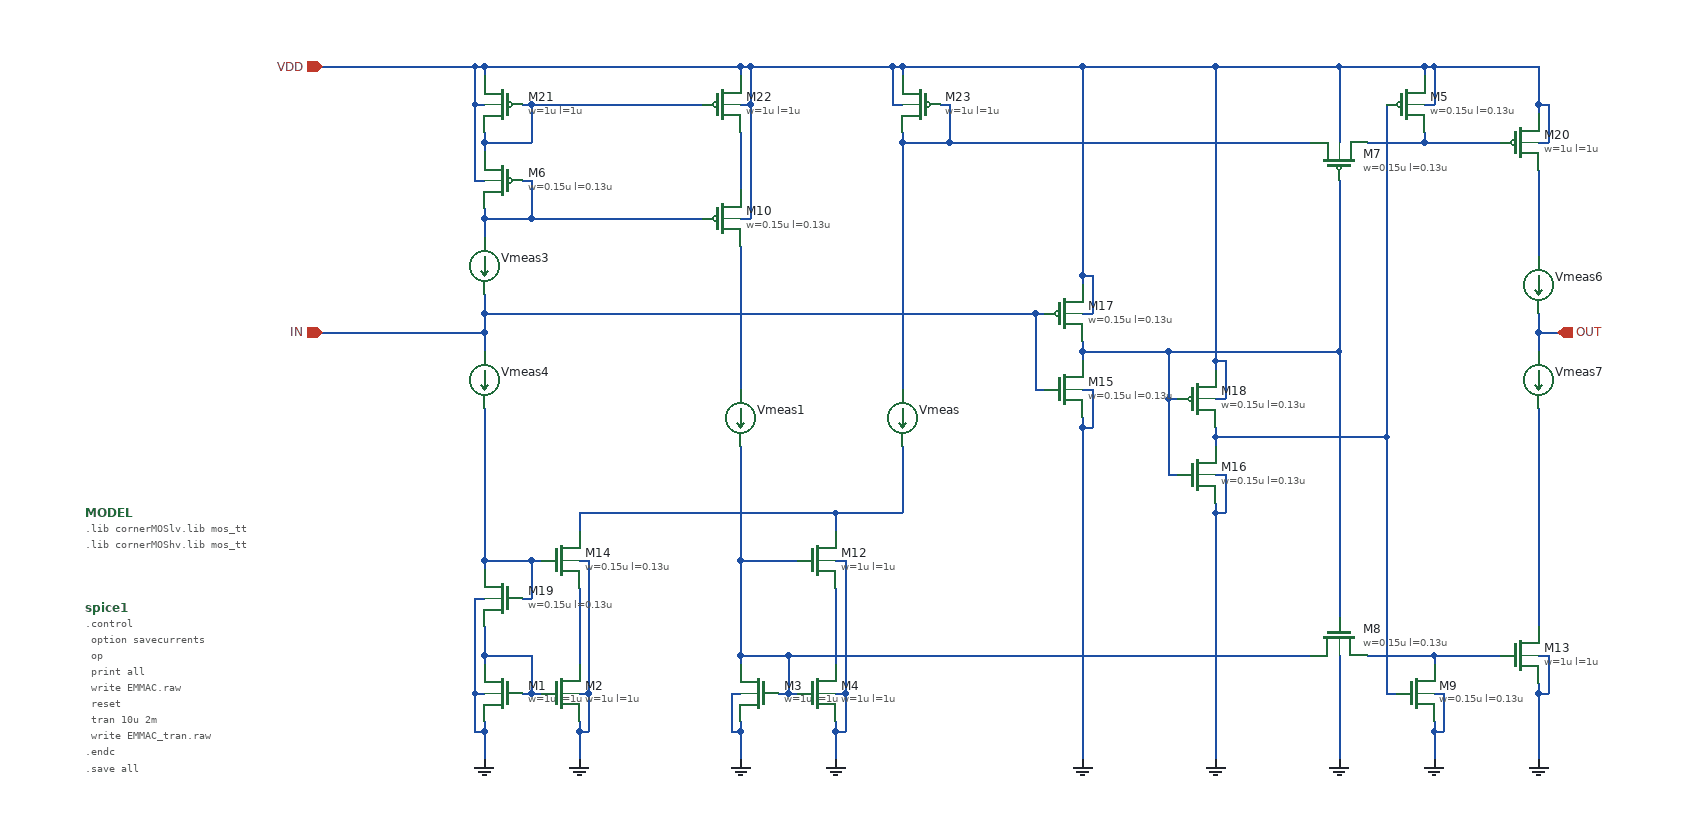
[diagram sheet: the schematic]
v {xschem version=3.4.8RC file_version=1.3}
G {}
K {}
V {}
S {}
F {}
E {}
N 390 280 400 280 {lab=#net1}
N 330 280 340 280 {lab=GND}
N 330 280 330 320 {lab=GND}
N 330 320 340 320 {lab=GND}
N 340 310 340 320 {lab=GND}
N 330 -380 330 -340 {lab=VDD}
N 330 -380 340 -380 {lab=VDD}
N 340 -380 340 -370 {lab=VDD}
N 380 -340 390 -340 {lab=#net2}
N 390 -340 390 -300 {lab=#net2}
N 340 -300 390 -300 {lab=#net2}
N 340 -310 340 -300 {lab=#net2}
N 610 -380 610 -370 {lab=VDD}
N 390 -340 570 -340 {lab=#net2}
N 610 -340 620 -340 {lab=VDD}
N 620 -380 620 -340 {lab=VDD}
N 610 -380 620 -380 {lab=VDD}
N 440 280 450 280 {lab=#net3}
N 450 280 450 320 {lab=#net3}
N 440 320 450 320 {lab=#net3}
N 440 310 440 320 {lab=#net3}
N 330 -340 340 -340 {lab=VDD}
N 380 180 390 180 {lab=#net4}
N 390 140 390 180 {lab=#net4}
N 440 320 440 350 {lab=#net3}
N 340 320 340 350 {lab=GND}
N 390 240 390 280 {lab=#net1}
N 380 280 390 280 {lab=#net1}
N 650 280 660 280 {lab=#net5}
N 660 240 660 280 {lab=#net5}
N 600 280 610 280 {lab=#net6}
N 600 280 600 320 {lab=#net6}
N 600 320 610 320 {lab=#net6}
N 610 310 610 320 {lab=#net6}
N 710 280 720 280 {lab=#net7}
N 720 280 720 320 {lab=#net7}
N 710 320 720 320 {lab=#net7}
N 710 310 710 320 {lab=#net7}
N 710 320 710 350 {lab=#net7}
N 610 320 610 350 {lab=#net6}
N 660 280 670 280 {lab=#net5}
N 770 -380 770 -340 {lab=VDD}
N 770 -380 780 -380 {lab=VDD}
N 780 -380 780 -370 {lab=VDD}
N 820 -340 830 -340 {lab=#net8}
N 770 -340 780 -340 {lab=VDD}
N 1450 240 1460 240 {lab=#net9}
N 340 -120 340 -100 {lab=IN}
N 1450 -100 1470 -100 {lab=OUT}
N 330 180 340 180 {lab=GND}
N 1110 50 1120 50 {lab=#net10}
N 1120 50 1120 90 {lab=#net10}
N 1110 90 1120 90 {lab=#net10}
N 1110 -70 1110 -60 {lab=VDD}
N 1110 -30 1120 -30 {lab=VDD}
N 1120 -70 1120 -30 {lab=VDD}
N 1110 -70 1120 -70 {lab=VDD}
N 1060 50 1070 50 {lab=#net11}
N 1060 -30 1070 -30 {lab=#net11}
N 620 -380 770 -380 {lab=VDD}
N 830 -340 830 -300 {lab=#net8}
N 1460 240 1460 280 {lab=#net9}
N 1450 280 1460 280 {lab=#net9}
N 1450 270 1450 280 {lab=#net9}
N 1330 -380 1330 -370 {lab=VDD}
N 1330 -340 1340 -340 {lab=VDD}
N 1340 -380 1340 -340 {lab=VDD}
N 1330 -380 1340 -380 {lab=VDD}
N 1240 -380 1330 -380 {lab=VDD}
N 1340 -380 1450 -380 {lab=VDD}
N 1340 280 1350 280 {lab=#net12}
N 1350 280 1350 320 {lab=#net12}
N 1340 310 1340 320 {lab=#net12}
N 1340 320 1350 320 {lab=#net12}
N 1240 -380 1240 -300 {lab=VDD}
N 1330 -300 1410 -300 {lab=#net13}
N 1330 -310 1330 -300 {lab=#net13}
N 1270 -300 1330 -300 {lab=#net13}
N 1450 280 1450 350 {lab=#net9}
N 1340 240 1410 240 {lab=#net14}
N 1240 240 1240 350 {lab=#net15}
N 1340 240 1340 250 {lab=#net14}
N 1270 240 1340 240 {lab=#net14}
N 1340 320 1340 350 {lab=#net12}
N 1290 280 1300 280 {lab=#net16}
N 780 -300 780 -40 {lab=#net8}
N 780 20 780 90 {lab=#net17}
N 340 -300 340 -290 {lab=#net2}
N 340 240 340 250 {lab=#net1}
N 1450 -300 1460 -300 {lab=VDD}
N 1460 -340 1460 -300 {lab=VDD}
N 1450 -340 1450 -330 {lab=VDD}
N 1450 -340 1460 -340 {lab=VDD}
N 1450 -380 1450 -340 {lab=VDD}
N 1290 10 1290 280 {lab=#net16}
N 1110 10 1290 10 {lab=#net16}
N 1110 0 1110 10 {lab=#net16}
N 780 -300 830 -300 {lab=#net8}
N 780 -310 780 -300 {lab=#net8}
N 830 -300 1210 -300 {lab=#net8}
N 170 -380 330 -380 {lab=VDD}
N 340 240 390 240 {lab=#net1}
N 170 -100 340 -100 {lab=IN}
N 1450 -270 1450 -180 {lab=#net18}
N 1450 -120 1450 -100 {lab=OUT}
N 1450 -100 1450 -80 {lab=OUT}
N 1450 -20 1450 210 {lab=#net19}
N 340 -100 340 -80 {lab=IN}
N 330 180 330 280 {lab=GND}
N 610 -220 620 -220 {lab=VDD}
N 620 -340 620 -220 {lab=VDD}
N 610 -310 610 -250 {lab=#net20}
N 610 -190 610 -40 {lab=#net21}
N 340 -380 610 -380 {lab=VDD}
N 610 240 610 250 {lab=#net5}
N 710 140 720 140 {lab=#net7}
N 610 140 670 140 {lab=#net5}
N 610 140 610 240 {lab=#net5}
N 610 240 660 240 {lab=#net5}
N 660 240 1210 240 {lab=#net5}
N 970 -80 970 -70 {lab=#net11}
N 970 -80 1060 -80 {lab=#net11}
N 970 -90 970 -80 {lab=#net11}
N 1060 -30 1060 50 {lab=#net11}
N 1060 -80 1060 -30 {lab=#net11}
N 970 -160 970 -150 {lab=VDD}
N 970 -160 980 -160 {lab=VDD}
N 980 -160 980 -120 {lab=VDD}
N 970 -120 980 -120 {lab=VDD}
N 920 -40 930 -40 {lab=IN}
N 920 -120 920 -40 {lab=IN}
N 920 -120 930 -120 {lab=IN}
N 970 -40 980 -40 {lab=#net22}
N 980 -40 980 0 {lab=#net22}
N 970 -10 970 0 {lab=#net22}
N 970 0 980 0 {lab=#net22}
N 1060 -80 1240 -80 {lab=#net11}
N 1240 -80 1240 200 {lab=#net11}
N 1110 -380 1240 -380 {lab=VDD}
N 1290 -340 1290 10 {lab=#net16}
N 1240 -260 1240 -80 {lab=#net11}
N 970 0 970 350 {lab=#net22}
N 1110 90 1110 350 {lab=#net10}
N 1110 80 1110 90 {lab=#net10}
N 1110 10 1110 20 {lab=#net16}
N 1110 -380 1110 -70 {lab=VDD}
N 970 -380 1110 -380 {lab=VDD}
N 970 -380 970 -160 {lab=VDD}
N 780 -380 970 -380 {lab=VDD}
N 340 -120 920 -120 {lab=IN}
N 340 -220 340 -200 {lab=#net23}
N 340 -140 340 -120 {lab=IN}
N 390 -220 570 -220 {lab=#net23}
N 340 -230 340 -220 {lab=#net23}
N 380 -260 390 -260 {lab=#net23}
N 390 -260 390 -220 {lab=#net23}
N 340 -220 390 -220 {lab=#net23}
N 330 -260 340 -260 {lab=VDD}
N 330 -340 330 -260 {lab=VDD}
N 340 210 340 240 {lab=#net1}
N 340 140 340 150 {lab=#net4}
N 340 140 390 140 {lab=#net4}
N 340 -20 340 140 {lab=#net4}
N 390 140 400 140 {lab=#net4}
N 440 170 440 250 {lab=#net24}
N 450 140 450 280 {lab=#net3}
N 440 140 450 140 {lab=#net3}
N 440 90 440 110 {lab=#net17}
N 710 90 780 90 {lab=#net17}
N 610 20 610 140 {lab=#net5}
N 710 90 710 110 {lab=#net17}
N 440 90 710 90 {lab=#net17}
N 720 140 720 280 {lab=#net7}
N 710 170 710 250 {lab=#net25}
C {devices/code_shown.sym} -80 90 0 0 {name=MODEL only_toplevel=true
format="tcleval( @value )"
value="
.lib cornerMOSlv.lib mos_tt
.lib cornerMOShv.lib mos_tt
"}
C {code_shown.sym} -80 190 0 0 {name=spice1 only_toplevel=true value="
.control
	option savecurrents
	op
	print all
	write EMMAC.raw
	reset
	tran 10u 2m
	write EMMAC_tran.raw
.endc

.save all
"}
C {gnd.sym} 340 350 0 0 {name=l6 lab=GND}
C {sg13g2_pr/sg13_lv_nmos.sym} 360 280 0 1 {name=M1
l=1u
w=1u
ng=1
m=1
model=sg13_lv_nmos
spiceprefix=X
}
C {sg13g2_pr/sg13_lv_nmos.sym} 420 280 0 0 {name=M2
l=1u
w=1u
ng=1
m=1
model=sg13_lv_nmos
spiceprefix=X
}
C {sg13g2_pr/sg13_lv_pmos.sym} 360 -340 0 1 {name=M21
l=1u
w=1u
ng=1
m=1
model=sg13_lv_pmos
spiceprefix=X
}
C {sg13g2_pr/sg13_lv_pmos.sym} 590 -340 0 0 {name=M22
l=1u
w=1u
ng=1
m=1
model=sg13_lv_pmos
spiceprefix=X
}
C {sg13g2_pr/sg13_lv_nmos.sym} 630 280 0 1 {name=M3
l=1u
w=1u
ng=1
m=1
model=sg13_lv_nmos
spiceprefix=X
}
C {sg13g2_pr/sg13_lv_nmos.sym} 690 280 0 0 {name=M4
l=1u
w=1u
ng=1
m=1
model=sg13_lv_nmos
spiceprefix=X
}
C {sg13g2_pr/sg13_lv_pmos.sym} 800 -340 0 1 {name=M23
l=1u
w=1u
ng=1
m=1
model=sg13_lv_pmos
spiceprefix=X
}
C {sg13g2_pr/sg13_lv_pmos.sym} 1430 -300 0 0 {name=M20
l=1u
w=1u
ng=1
m=\{wmul\}
model=sg13_lv_pmos
spiceprefix=X
}
C {sg13g2_pr/sg13_lv_nmos.sym} 1430 240 0 0 {name=M13
l=1u
w=1u
ng=1
m=\{wmul\}
model=sg13_lv_nmos
spiceprefix=X
}
C {sg13g2_pr/sg13_lv_nmos.sym} 950 -40 0 0 {name=M15
l=0.13u
w=0.15u
ng=1
m=1
model=sg13_lv_nmos
spiceprefix=X
}
C {sg13g2_pr/sg13_lv_pmos.sym} 950 -120 0 0 {name=M17
l=0.13u
w=0.15u
ng=1
m=1
model=sg13_lv_pmos
spiceprefix=X
}
C {opin.sym} 1470 -100 0 0 {name=p2 lab=OUT}
C {ipin.sym} 170 -100 0 0 {name=p4 lab=IN}
C {ipin.sym} 170 -380 0 0 {name=p5 lab=VDD}
C {sg13g2_pr/sg13_lv_nmos.sym} 1090 50 0 0 {name=M16
l=0.13u
w=0.15u
ng=1
m=1
model=sg13_lv_nmos
spiceprefix=X
}
C {sg13g2_pr/sg13_lv_pmos.sym} 1090 -30 0 0 {name=M18
l=0.13u
w=0.15u
ng=1
m=1
model=sg13_lv_pmos
spiceprefix=X
}
C {ammeter.sym} 780 -10 0 0 {name=Vmeas savecurrent=true spice_ignore=0}
C {ammeter.sym} 340 -170 0 0 {name=Vmeas3 savecurrent=true spice_ignore=0}
C {ammeter.sym} 340 -50 0 0 {name=Vmeas4 savecurrent=true spice_ignore=0}
C {ammeter.sym} 1450 -150 0 0 {name=Vmeas6 savecurrent=true spice_ignore=0}
C {ammeter.sym} 1450 -50 0 0 {name=Vmeas7 savecurrent=true spice_ignore=0}
C {sg13g2_pr/sg13_lv_nmos.sym} 360 180 0 1 {name=M19
l=0.13u
w=0.15u
ng=1
m=1
model=sg13_lv_nmos
spiceprefix=X
}
C {ammeter.sym} 610 -10 0 0 {name=Vmeas1 savecurrent=true spice_ignore=0}
C {sg13g2_pr/sg13_lv_pmos.sym} 1240 -280 3 0 {name=M7
l=0.13u
w=0.15u
ng=1
m=1
model=sg13_lv_pmos
spiceprefix=X
}
C {sg13g2_pr/sg13_lv_pmos.sym} 1310 -340 0 0 {name=M5
l=0.13u
w=0.15u
ng=1
m=1
model=sg13_lv_pmos
spiceprefix=X
}
C {sg13g2_pr/sg13_lv_nmos.sym} 1240 220 1 0 {name=M8
l=0.13u
w=0.15u
ng=1
m=1
model=sg13_lv_nmos
spiceprefix=X
}
C {sg13g2_pr/sg13_lv_nmos.sym} 1320 280 0 0 {name=M9
l=0.13u
w=0.15u
ng=1
m=1
model=sg13_lv_nmos
spiceprefix=X
}
C {sg13g2_pr/sg13_lv_nmos.sym} 420 140 0 0 {name=M14
l=0.13u
w=0.15u
ng=1
m=1
model=sg13_lv_nmos
spiceprefix=X
}
C {sg13g2_pr/sg13_lv_pmos.sym} 360 -260 0 1 {name=M6
l=0.13u
w=0.15u
ng=1
m=1
model=sg13_lv_pmos
spiceprefix=X
}
C {sg13g2_pr/sg13_lv_nmos.sym} 690 140 0 0 {name=M12
l=1u
w=1u
ng=1
m=1
model=sg13_lv_nmos
spiceprefix=X
}
C {sg13g2_pr/sg13_lv_pmos.sym} 590 -220 0 0 {name=M10
l=0.13u
w=0.15u
ng=1
m=1
model=sg13_lv_pmos
spiceprefix=X
}
C {gnd.sym} 440 350 0 0 {name=l1 lab=GND}
C {gnd.sym} 610 350 0 0 {name=l2 lab=GND}
C {gnd.sym} 710 350 0 0 {name=l3 lab=GND}
C {gnd.sym} 970 350 0 0 {name=l4 lab=GND}
C {gnd.sym} 1110 350 0 0 {name=l5 lab=GND}
C {gnd.sym} 1240 350 0 0 {name=l7 lab=GND}
C {gnd.sym} 1340 350 0 0 {name=l8 lab=GND}
C {gnd.sym} 1450 350 0 0 {name=l9 lab=GND}
